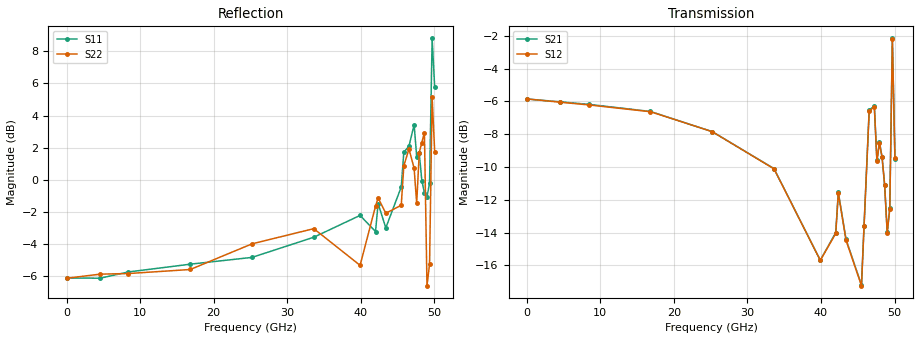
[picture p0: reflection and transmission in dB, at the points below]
! 10/31/2025 3:18:30 PM
! C:\MESURES\046-TRL-DUT-CHEP0603\DUT\DUT-2542B6-CHEP0603N-3-I.S2P
! CHANNEL.1 Sparams
! TR.MEASUREMENT
! CORRECTED.DATA
! RF.CORRECTION: CAL.A: FULL.TWO.PORT.CALCAL.A: Port 1,4
! AVERAGING.OFF
! IF.BANDWIDTH: 500HZ
! SWEEPTYPE:  FREQ.SWEEP(Linear)
! Reference Plane Port Info
! PORT:  PORT1  PORT4
! DISTANCE:  0  m  0  m
! TIME:  0  s  0  s
! PHASE.OFFSET:  0  deg.  0  deg.
! LOSS:  0  dB  0  dB
! REF.LOSS:  0  dB  0  dB
! REF.FREQ:  0  Hz  0  Hz
! Power Info
! POWER:  -10  dBm  -10  dBm
! EFF.POWER:  -10  dBm  -10  dBm
! SOURCE.ATTEN:  0  dB  0  dB
! TEST.ATTEN:  0  dB  0  dB
! PORTZ: Port1:50 Port4:50
# GHZ S RI R 50
! FREQ.GHZ  S11RE  S11IM  S41RE  S41IM  S14RE  S14IM  S44RE  S44IM
!; PortSelection: Port_14 (1-->1,4-->4)
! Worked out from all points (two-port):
!   144 points, 10 MHz to 50.05 GHz, reference 50 ohm
!   highest |S21| = -2.16 dB at 49.7 GHz (marker M1); lowest = -17.2 dB at 45.5 GHz (marker M2)
!   |S21| within 3 dB of the highest: 49.60134 GHz to 49.84562 GHz (244.3 MHz wide, 0.491 % of centre)
!   lowest |S11| = -6.1 dB at 4.559 GHz (marker M3), VSWR 2.96, Z = 144 - j23.6 ohm
!   |S11| at or under -10 dB: nowhere
!   |S22| runs from -6.6 to 5.1 dB; largest |S21 - S12| = 0.0075
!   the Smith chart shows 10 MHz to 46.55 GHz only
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0.01  0.4952 0.0175  0.5093 -0.0167  0.5094 -0.0169  0.4944 0.0173
4.55935  0.491 -0.062  0.4946 -0.0694  0.4934 -0.068  0.5062 -0.0569
8.4088  0.5081 -0.098  0.4754 -0.1215  0.4737 -0.1207  0.5005 -0.1063
16.8076  0.4987 -0.2249  0.4092 -0.2248  0.4084 -0.2244  0.4974 -0.1731
25.2064  0.4724 -0.3266  0.297 -0.2756  0.2962 -0.2764  0.5669 -0.281
33.6052  0.5037 -0.4316  0.1975 -0.2424  0.1969 -0.2422  0.5981 -0.3741
39.9043  0.4614 -0.6234  0.1389 -0.088  0.1388 -0.0876  0.4253 -0.3369
42.004  0.6211 -0.3026  0.1889 -0.0643  0.1879 -0.0635  0.7646 -0.3183
42.35395  0.6338 -0.5576  0.211 -0.1603  0.2103 -0.1583  0.5415 -0.6921
43.4038  0.192 -0.6831  0.1176 -0.1495  0.1167 -0.1486  0.3675 -0.6968
45.5035  0.683 -0.6611  0.1355 0.0271  0.1347 0.0275  0.7015 -0.4509
45.85345  1.004 -0.6911  0.1527 0.1434  0.1519 0.1433  0.9259 -0.6057
46.55335  0.876 -0.923  0.4694 0.0523  0.4656 0.0513  0.7353 -1.008
47.25325  0.8707 -1.202  0.3351 -0.3498  0.3355 -0.3466  0.1063 -1.082
47.6032  0.4649 -1.086  0.2147 -0.2519  0.2143 -0.2501  0.1634 -0.8295
47.95315  0.7988 -0.9076  0.3224 -0.1943  0.3209 -0.1937  0.4746 -1.12
48.3031  0.5685 -0.8149  0.2744 -0.1984  0.2744 -0.1978  0.4847 -1.213
48.65305  0.7452 -0.5276  0.2754 -0.0434  0.2755 -0.0423  0.9365 -1.045
49.003  0.632 0.6181  -0.0102 -0.1997  -0.00917 -0.1992  0.2969 0.3631
49.35295  0.2765 0.9395  0.097 -0.2164  0.0972 -0.2144  0.0685 0.5428
49.7029  2.203 1.651  -0.4786 -0.6155  -0.4723 -0.6159  1.186 1.363
50.05285  1.743 0.846  -0.2436 -0.2289  -0.2468 -0.2284  1.058 0.6088
